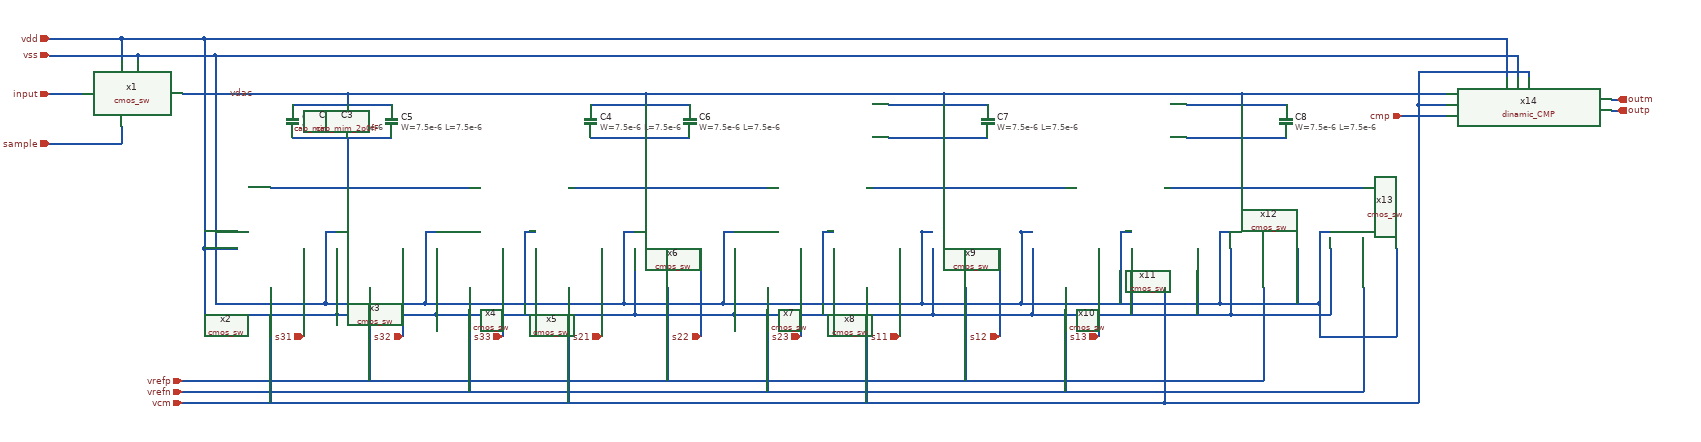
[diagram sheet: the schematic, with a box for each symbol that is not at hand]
v {xschem version=3.4.5 file_version=1.2
}
G {}
K {}
V {}
S {}
E {}
N -490 -240 -490 -200 {
lab=vdd}
N -490 -240 -340 -240 {
lab=vdd}
N -340 -240 -340 140 {
lab=vdd}
N -340 140 -280 140 {
lab=vdd}
N -340 140 -340 260 {
lab=vdd}
N -340 260 -100 260 {
lab=vdd}
N -100 140 -100 260 {
lab=vdd}
N -100 260 80 260 {
lab=vdd}
N 80 140 80 260 {
lab=vdd}
N -120 110 -100 110 {
lab=vss}
N -120 110 -120 240 {
lab=vss}
N -320 240 -120 240 {
lab=vss}
N -320 -210 -320 240 {
lab=vss}
N -460 -210 -320 -210 {
lab=vss}
N -460 -210 -460 -200 {
lab=vss}
N -120 240 60 240 {
lab=vss}
N 60 110 60 240 {
lab=vss}
N 60 110 80 110 {
lab=vss}
N -220 30 140 30 {
lab=#net1}
N -180 -60 0 -60 {
lab=#net1}
N -80 -60 -80 30 {
lab=#net1}
N -180 -120 -0 -120 {
lab=vdac}
N -380 -140 -80 -140 {
lab=vdac}
N -80 -140 -80 -120 {
lab=vdac}
N -160 140 -160 300 {
lab=s31}
N 20 140 20 300 {
lab=s32}
N 200 140 200 300 {
lab=s33}
N -620 -240 -490 -240 {
lab=vdd}
N -620 -210 -460 -210 {
lab=vss}
N -620 -140 -560 -140 {
lab=input}
N -620 -50 -490 -50 {
lab=sample}
N -490 -80 -490 -50 {
lab=sample}
N -320 110 -280 110 {
lab=vss}
N 440 140 440 260 {
lab=vdd}
N 440 260 620 260 {
lab=vdd}
N 620 140 620 260 {
lab=vdd}
N 420 110 440 110 {
lab=vss}
N 420 110 420 240 {
lab=vss}
N 220 240 420 240 {
lab=vss}
N 420 240 600 240 {
lab=vss}
N 600 110 600 240 {
lab=vss}
N 600 110 620 110 {
lab=vss}
N 320 30 680 30 {
lab=#net2}
N 360 -60 540 -60 {
lab=#net2}
N 460 -60 460 30 {
lab=#net2}
N 360 -120 540 -120 {
lab=vdac}
N 160 -140 460 -140 {
lab=vdac}
N 460 -140 460 -120 {
lab=vdac}
N 380 140 380 300 {
lab=s21}
N 560 140 560 300 {
lab=s22}
N 740 140 740 300 {
lab=s23}
N 980 140 980 260 {
lab=vdd}
N 980 260 1160 260 {
lab=vdd}
N 1160 140 1160 260 {
lab=vdd}
N 960 110 980 110 {
lab=vss}
N 960 110 960 240 {
lab=vss}
N 760 240 960 240 {
lab=vss}
N 960 240 1140 240 {
lab=vss}
N 1140 110 1140 240 {
lab=vss}
N 1140 110 1160 110 {
lab=vss}
N 860 30 1220 30 {
lab=#net3}
N 900 -60 1080 -60 {
lab=#net3}
N 1000 -60 1000 30 {
lab=#net3}
N 900 -120 1080 -120 {
lab=vdac}
N 700 -140 1000 -140 {
lab=vdac}
N 1000 -140 1000 -120 {
lab=vdac}
N 920 140 920 300 {
lab=s11}
N 1100 140 1100 300 {
lab=s12}
N 1280 140 1280 300 {
lab=s13}
N 1520 140 1520 260 {
lab=vdd}
N 1520 260 1700 260 {
lab=vdd}
N 1700 140 1700 260 {
lab=vdd}
N 1500 110 1520 110 {
lab=vss}
N 1500 110 1500 240 {
lab=vss}
N 1300 240 1500 240 {
lab=vss}
N 1500 240 1680 240 {
lab=vss}
N 1680 110 1680 240 {
lab=vss}
N 1680 110 1700 110 {
lab=vss}
N 1400 30 1760 30 {
lab=#net4}
N 1440 -60 1620 -60 {
lab=#net4}
N 1540 -60 1540 30 {
lab=#net4}
N 1440 -120 1620 -120 {
lab=vdac}
N 1240 -140 1540 -140 {
lab=vdac}
N 1540 -140 1540 -120 {
lab=vdac}
N 1820 140 1820 300 {
lab=vss}
N -80 -140 160 -140 {
lab=vdac}
N 460 -140 700 -140 {
lab=vdac}
N 1000 -140 1240 -140 {
lab=vdac}
N 1140 240 1300 240 {
lab=vss}
N 1160 260 1520 260 {
lab=vdd}
N 620 260 980 260 {
lab=vdd}
N 600 240 760 240 {
lab=vss}
N 60 240 220 240 {
lab=vss}
N 80 260 440 260 {
lab=vdd}
N 260 140 260 260 {
lab=vdd}
N 240 110 240 240 {
lab=vss}
N 240 110 260 110 {
lab=vss}
N 800 140 800 260 {
lab=vdd}
N 780 110 780 240 {
lab=vss}
N 780 110 800 110 {
lab=vss}
N 980 140 980 260 {
lab=vdd}
N 960 110 960 240 {
lab=vss}
N 960 110 980 110 {
lab=vss}
N 1160 140 1160 260 {
lab=vdd}
N 1140 110 1140 240 {
lab=vss}
N 1140 110 1160 110 {
lab=vss}
N 1340 140 1340 260 {
lab=vdd}
N 1320 110 1320 240 {
lab=vss}
N 1320 110 1340 110 {
lab=vss}
N -380 420 1400 420 {
lab=vcm}
N 1400 210 1400 420 {
lab=vcm}
N -380 380 1580 380 {
lab=vrefp}
N 1580 210 1580 380 {
lab=vrefp}
N 1760 210 1760 400 {
lab=vrefn}
N -380 400 1760 400 {
lab=vrefn}
N -40 210 -40 380 {
lab=vrefp}
N 140 210 140 400 {
lab=vrefn}
N -220 210 -220 420 {
lab=vcm}
N 500 210 500 380 {
lab=vrefp}
N 680 210 680 400 {
lab=vrefn}
N 320 210 320 420 {
lab=vcm}
N 1040 210 1040 380 {
lab=vrefp}
N 1220 210 1220 400 {
lab=vrefn}
N 860 210 860 420 {
lab=vcm}
N 1680 240 1680 300 {
lab=vss}
N 1460 140 1460 260 {
lab=vdd}
N 1640 140 1640 240 {
lab=vss}
N 1680 300 1820 300 {
lab=vss}
N 1540 -140 1910 -140 {
lab=vdac}
N 1860 -120 1910 -120 {
lab=vcm}
N 1860 -120 1860 420 {
lab=vcm}
N 1400 420 1860 420 {
lab=vcm}
N -320 -210 2040 -210 {
lab=vss}
N 2040 -210 2040 -170 {
lab=vss}
N 1860 -180 1860 -120 {
lab=vcm}
N 1860 -180 2060 -180 {
lab=vcm}
N 2060 -180 2060 -170 {
lab=vcm}
N 2020 -240 2020 -170 {
lab=vdd}
N -340 -240 2020 -240 {
lab=vdd}
N 1830 -100 1910 -100 {
lab=cmp}
N 2210 -130 2220 -130 {
lab=outm}
N 2210 -110 2220 -110 {
lab=outp}
C {cmos_sw.sym} -470 -140 0 0 {name=x1}
C {cmos_sw.sym} -220 120 3 0 {name=x2}
C {cmos_sw.sym} -40 120 3 0 {name=x3}
C {cmos_sw.sym} 140 120 3 0 {name=x4}
C {devices/ipin.sym} -160 300 3 0 {name=p1 lab=s31}
C {devices/ipin.sym} 20 300 3 0 {name=p2 lab=s32}
C {devices/ipin.sym} 200 300 3 0 {name=p3 lab=s33}
C {devices/iopin.sym} -620 -240 2 0 {name=p4 lab=vdd}
C {devices/iopin.sym} -620 -210 2 0 {name=p5 lab=vss}
C {devices/iopin.sym} -380 380 2 0 {name=p6 lab=vrefp}
C {devices/iopin.sym} -380 400 2 0 {name=p7 lab=vrefn}
C {devices/iopin.sym} -380 420 2 0 {name=p8 lab=vcm}
C {devices/ipin.sym} -620 -140 0 0 {name=p9 lab=input}
C {devices/ipin.sym} -620 -50 0 0 {name=p10 lab=sample}
C {cmos_sw.sym} 320 120 3 0 {name=x5}
C {cmos_sw.sym} 500 120 3 0 {name=x6}
C {cmos_sw.sym} 680 120 3 0 {name=x7}
C {devices/ipin.sym} 380 300 3 0 {name=p11 lab=s21}
C {devices/ipin.sym} 560 300 3 0 {name=p12 lab=s22}
C {devices/ipin.sym} 740 300 3 0 {name=p13 lab=s23}
C {cmos_sw.sym} 860 120 3 0 {name=x8}
C {cmos_sw.sym} 1040 120 3 0 {name=x9}
C {cmos_sw.sym} 1220 120 3 0 {name=x10}
C {devices/ipin.sym} 920 300 3 0 {name=p14 lab=s11}
C {devices/ipin.sym} 1100 300 3 0 {name=p15 lab=s12}
C {devices/ipin.sym} 1280 300 3 0 {name=p16 lab=s13}
C {cmos_sw.sym} 1400 120 3 0 {name=x11}
C {cmos_sw.sym} 1580 120 3 0 {name=x12}
C {cmos_sw.sym} 1760 120 3 0 {name=x13}
C {dinamic_CMP.sym} 2060 -100 0 0 {name=x14}
C {devices/ipin.sym} 1830 -100 0 0 {name=p17 lab=cmp}
C {devices/opin.sym} 2220 -130 0 0 {name=p18 lab=outm}
C {devices/opin.sym} 2220 -110 0 0 {name=p19 lab=outp}
C {devices/lab_pin.sym} -250 -140 3 0 {name=p20 sig_type=std_logic lab=vdac
}
C {symbols/cap_mim_2p0fF.sym} 0 -90 0 0 {name=C5
W=7.5e-6
L=7.5e-6
model=cap_mim_2f0fF
spiceprefix=X
m=1}
C {symbols/cap_mim_2p0fF.sym} -180 -90 0 0 {name=C1
W=7.5e-6
L=7.5e-6
model=cap_mim_2f0fF
spiceprefix=X
m=1}
C {symbols/cap_mim_2p0fF.sym} -120 -90 0 0 {name=C2
W=7.5e-6
L=7.5e-6
model=cap_mim_2f0fF
spiceprefix=X
m=1}
C {symbols/cap_mim_2p0fF.sym} -60 -90 0 0 {name=C3
W=7.5e-6
L=7.5e-6
model=cap_mim_2f0fF
spiceprefix=X
m=1}
C {symbols/cap_mim_2p0fF.sym} 360 -90 0 0 {name=C4
W=7.5e-6
L=7.5e-6
model=cap_mim_2f0fF
spiceprefix=X
m=1}
C {symbols/cap_mim_2p0fF.sym} 540 -90 0 0 {name=C6
W=7.5e-6
L=7.5e-6
model=cap_mim_2f0fF
spiceprefix=X
m=1}
C {symbols/cap_mim_2p0fF.sym} 1080 -90 0 0 {name=C7
W=7.5e-6
L=7.5e-6
model=cap_mim_2f0fF
spiceprefix=X
m=1}
C {symbols/cap_mim_2p0fF.sym} 1620 -90 0 0 {name=C8
W=7.5e-6
L=7.5e-6
model=cap_mim_2f0fF
spiceprefix=X
m=1}
